VERSION 5.7 ;
  NOWIREEXTENSIONATPIN ON ;
  DIVIDERCHAR "/" ;
  BUSBITCHARS "[]" ;
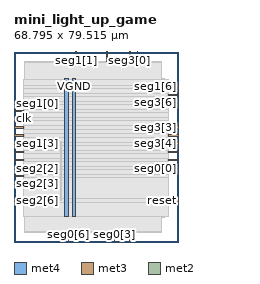
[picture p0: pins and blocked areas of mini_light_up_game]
MACRO mini_light_up_game
  CLASS BLOCK ;
  FOREIGN mini_light_up_game ;
  ORIGIN 0.000 0.000 ;
  SIZE 68.795 BY 79.515 ;
  PIN VGND
    DIRECTION INOUT ;
    USE GROUND ;
    PORT
      LAYER met4 ;
        RECT 24.340 10.640 25.940 68.240 ;
    END
  END VGND
  PIN VPWR
    DIRECTION INOUT ;
    USE POWER ;
    PORT
      LAYER met4 ;
        RECT 21.040 10.640 22.640 68.240 ;
    END
  END VPWR
  PIN btn
    DIRECTION INPUT ;
    USE SIGNAL ;
    ANTENNAGATEAREA 0.196500 ;
    PORT
      LAYER met3 ;
        RECT 64.795 37.440 68.795 38.040 ;
    END
  END btn
  PIN clk
    DIRECTION INPUT ;
    USE SIGNAL ;
    ANTENNAGATEAREA 0.852000 ;
    PORT
      LAYER met3 ;
        RECT 0.000 54.440 4.000 55.040 ;
    END
  END clk
  PIN reset
    DIRECTION INPUT ;
    USE SIGNAL ;
    ANTENNAGATEAREA 0.196500 ;
    PORT
      LAYER met3 ;
        RECT 64.795 17.040 68.795 17.640 ;
    END
  END reset
  PIN seg0[0]
    DIRECTION OUTPUT ;
    USE SIGNAL ;
    ANTENNADIFFAREA 0.445500 ;
    PORT
      LAYER met3 ;
        RECT 64.795 30.640 68.795 31.240 ;
    END
  END seg0[0]
  PIN seg0[1]
    DIRECTION OUTPUT ;
    USE SIGNAL ;
    ANTENNADIFFAREA 0.445500 ;
    PORT
      LAYER met3 ;
        RECT 64.795 34.040 68.795 34.640 ;
    END
  END seg0[1]
  PIN seg0[2]
    DIRECTION OUTPUT ;
    USE SIGNAL ;
    ANTENNADIFFAREA 0.445500 ;
    PORT
      LAYER met2 ;
        RECT 38.730 0.000 39.010 4.000 ;
    END
  END seg0[2]
  PIN seg0[3]
    DIRECTION OUTPUT ;
    USE SIGNAL ;
    ANTENNADIFFAREA 0.445500 ;
    PORT
      LAYER met2 ;
        RECT 41.950 0.000 42.230 4.000 ;
    END
  END seg0[3]
  PIN seg0[4]
    DIRECTION OUTPUT ;
    USE SIGNAL ;
    ANTENNADIFFAREA 0.445500 ;
    PORT
      LAYER met2 ;
        RECT 45.170 0.000 45.450 4.000 ;
    END
  END seg0[4]
  PIN seg0[5]
    DIRECTION OUTPUT ;
    USE SIGNAL ;
    ANTENNADIFFAREA 0.445500 ;
    PORT
      LAYER met2 ;
        RECT 48.390 0.000 48.670 4.000 ;
    END
  END seg0[5]
  PIN seg0[6]
    DIRECTION OUTPUT ;
    USE SIGNAL ;
    PORT
      LAYER met2 ;
        RECT 22.630 0.000 22.910 4.000 ;
    END
  END seg0[6]
  PIN seg1[0]
    DIRECTION OUTPUT ;
    USE SIGNAL ;
    ANTENNADIFFAREA 0.445500 ;
    PORT
      LAYER met3 ;
        RECT 0.000 57.840 4.000 58.440 ;
    END
  END seg1[0]
  PIN seg1[1]
    DIRECTION OUTPUT ;
    USE SIGNAL ;
    ANTENNADIFFAREA 0.445500 ;
    PORT
      LAYER met2 ;
        RECT 25.850 75.515 26.130 79.515 ;
    END
  END seg1[1]
  PIN seg1[2]
    DIRECTION OUTPUT ;
    USE SIGNAL ;
    ANTENNADIFFAREA 0.445500 ;
    PORT
      LAYER met3 ;
        RECT 0.000 51.040 4.000 51.640 ;
    END
  END seg1[2]
  PIN seg1[3]
    DIRECTION OUTPUT ;
    USE SIGNAL ;
    ANTENNADIFFAREA 0.445500 ;
    PORT
      LAYER met3 ;
        RECT 0.000 40.840 4.000 41.440 ;
    END
  END seg1[3]
  PIN seg1[4]
    DIRECTION OUTPUT ;
    USE SIGNAL ;
    ANTENNADIFFAREA 0.445500 ;
    PORT
      LAYER met3 ;
        RECT 0.000 44.240 4.000 44.840 ;
    END
  END seg1[4]
  PIN seg1[5]
    DIRECTION OUTPUT ;
    USE SIGNAL ;
    ANTENNADIFFAREA 0.445500 ;
    PORT
      LAYER met3 ;
        RECT 0.000 47.640 4.000 48.240 ;
    END
  END seg1[5]
  PIN seg1[6]
    DIRECTION OUTPUT ;
    USE SIGNAL ;
    PORT
      LAYER met3 ;
        RECT 64.795 64.640 68.795 65.240 ;
    END
  END seg1[6]
  PIN seg2[0]
    DIRECTION OUTPUT ;
    USE SIGNAL ;
    ANTENNADIFFAREA 0.445500 ;
    PORT
      LAYER met3 ;
        RECT 0.000 37.440 4.000 38.040 ;
    END
  END seg2[0]
  PIN seg2[1]
    DIRECTION OUTPUT ;
    USE SIGNAL ;
    ANTENNADIFFAREA 0.445500 ;
    PORT
      LAYER met3 ;
        RECT 0.000 34.040 4.000 34.640 ;
    END
  END seg2[1]
  PIN seg2[2]
    DIRECTION OUTPUT ;
    USE SIGNAL ;
    ANTENNADIFFAREA 0.445500 ;
    PORT
      LAYER met3 ;
        RECT 0.000 30.640 4.000 31.240 ;
    END
  END seg2[2]
  PIN seg2[3]
    DIRECTION OUTPUT ;
    USE SIGNAL ;
    ANTENNADIFFAREA 0.445500 ;
    PORT
      LAYER met3 ;
        RECT 0.000 27.240 4.000 27.840 ;
    END
  END seg2[3]
  PIN seg2[4]
    DIRECTION OUTPUT ;
    USE SIGNAL ;
    ANTENNADIFFAREA 0.445500 ;
    PORT
      LAYER met2 ;
        RECT 19.410 0.000 19.690 4.000 ;
    END
  END seg2[4]
  PIN seg2[5]
    DIRECTION OUTPUT ;
    USE SIGNAL ;
    ANTENNADIFFAREA 0.445500 ;
    PORT
      LAYER met2 ;
        RECT 25.850 0.000 26.130 4.000 ;
    END
  END seg2[5]
  PIN seg2[6]
    DIRECTION OUTPUT ;
    USE SIGNAL ;
    PORT
      LAYER met3 ;
        RECT 0.000 17.040 4.000 17.640 ;
    END
  END seg2[6]
  PIN seg3[0]
    DIRECTION OUTPUT ;
    USE SIGNAL ;
    ANTENNADIFFAREA 0.445500 ;
    PORT
      LAYER met2 ;
        RECT 48.390 75.515 48.670 79.515 ;
    END
  END seg3[0]
  PIN seg3[1]
    DIRECTION OUTPUT ;
    USE SIGNAL ;
    ANTENNADIFFAREA 0.445500 ;
    PORT
      LAYER met2 ;
        RECT 51.610 75.515 51.890 79.515 ;
    END
  END seg3[1]
  PIN seg3[2]
    DIRECTION OUTPUT ;
    USE SIGNAL ;
    ANTENNADIFFAREA 0.445500 ;
    PORT
      LAYER met2 ;
        RECT 38.730 75.515 39.010 79.515 ;
    END
  END seg3[2]
  PIN seg3[3]
    DIRECTION OUTPUT ;
    USE SIGNAL ;
    ANTENNADIFFAREA 0.445500 ;
    PORT
      LAYER met3 ;
        RECT 64.795 47.640 68.795 48.240 ;
    END
  END seg3[3]
  PIN seg3[4]
    DIRECTION OUTPUT ;
    USE SIGNAL ;
    ANTENNADIFFAREA 0.445500 ;
    PORT
      LAYER met3 ;
        RECT 64.795 40.840 68.795 41.440 ;
    END
  END seg3[4]
  PIN seg3[5]
    DIRECTION OUTPUT ;
    USE SIGNAL ;
    ANTENNADIFFAREA 0.445500 ;
    PORT
      LAYER met3 ;
        RECT 64.795 44.240 68.795 44.840 ;
    END
  END seg3[5]
  PIN seg3[6]
    DIRECTION OUTPUT ;
    USE SIGNAL ;
    PORT
      LAYER met3 ;
        RECT 64.795 61.240 68.795 61.840 ;
    END
  END seg3[6]
  OBS
      LAYER nwell ;
        RECT 5.330 10.795 63.210 68.190 ;
      LAYER li1 ;
        RECT 5.520 10.795 63.020 68.085 ;
      LAYER met1 ;
        RECT 4.210 10.240 63.020 68.240 ;
      LAYER met2 ;
        RECT 4.230 75.235 25.570 75.515 ;
        RECT 26.410 75.235 38.450 75.515 ;
        RECT 39.290 75.235 48.110 75.515 ;
        RECT 48.950 75.235 51.330 75.515 ;
        RECT 52.170 75.235 61.550 75.515 ;
        RECT 4.230 4.280 61.550 75.235 ;
        RECT 4.230 4.000 19.130 4.280 ;
        RECT 19.970 4.000 22.350 4.280 ;
        RECT 23.190 4.000 25.570 4.280 ;
        RECT 26.410 4.000 38.450 4.280 ;
        RECT 39.290 4.000 41.670 4.280 ;
        RECT 42.510 4.000 44.890 4.280 ;
        RECT 45.730 4.000 48.110 4.280 ;
        RECT 48.950 4.000 61.550 4.280 ;
      LAYER met3 ;
        RECT 3.990 65.640 64.795 68.165 ;
        RECT 3.990 64.240 64.395 65.640 ;
        RECT 3.990 62.240 64.795 64.240 ;
        RECT 3.990 60.840 64.395 62.240 ;
        RECT 3.990 58.840 64.795 60.840 ;
        RECT 4.400 57.440 64.795 58.840 ;
        RECT 3.990 55.440 64.795 57.440 ;
        RECT 4.400 54.040 64.795 55.440 ;
        RECT 3.990 52.040 64.795 54.040 ;
        RECT 4.400 50.640 64.795 52.040 ;
        RECT 3.990 48.640 64.795 50.640 ;
        RECT 4.400 47.240 64.395 48.640 ;
        RECT 3.990 45.240 64.795 47.240 ;
        RECT 4.400 43.840 64.395 45.240 ;
        RECT 3.990 41.840 64.795 43.840 ;
        RECT 4.400 40.440 64.395 41.840 ;
        RECT 3.990 38.440 64.795 40.440 ;
        RECT 4.400 37.040 64.395 38.440 ;
        RECT 3.990 35.040 64.795 37.040 ;
        RECT 4.400 33.640 64.395 35.040 ;
        RECT 3.990 31.640 64.795 33.640 ;
        RECT 4.400 30.240 64.395 31.640 ;
        RECT 3.990 28.240 64.795 30.240 ;
        RECT 4.400 26.840 64.795 28.240 ;
        RECT 3.990 18.040 64.795 26.840 ;
        RECT 4.400 16.640 64.395 18.040 ;
        RECT 3.990 10.715 64.795 16.640 ;
      LAYER met4 ;
        RECT 19.615 17.175 19.945 41.985 ;
  END
END mini_light_up_game
END LIBRARY

